VERSION 5.8 ;
BUSBITCHARS "[]" ;
DIVIDERCHAR "/" ;

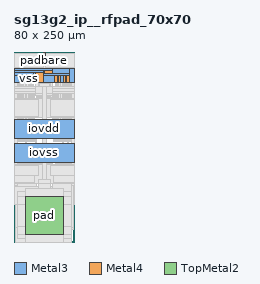
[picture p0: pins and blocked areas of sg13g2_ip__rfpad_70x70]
MACRO sg13g2_ip__rfpad_70x70
  CLASS PAD INOUT ;
  ORIGIN 0 0 ;
  FOREIGN sg13g2_ip__rfpad_70x70 0 0 ;
  SIZE 80.000 BY 250.000 ;
  SYMMETRY Y ;
  SITE sg13g2_ioSite ;
  PIN vss
    DIRECTION INOUT ;
    USE GROUND ;
    SHAPE ABUTMENT ;
    PORT
      LAYER Metal3 ;
      RECT 0.000 210.000 7.600 218.600 ;
      RECT 10.400 210.000 12.400 218.600 ;
      RECT 15.200 210.000 18.600 218.600 ;
      RECT 21.400 210.000 23.400 218.600 ;
      RECT 38.360 210.000 53.800 218.600 ;
      RECT 56.600 210.000 58.600 218.600 ;
      RECT 61.400 210.000 64.800 218.600 ;
      RECT 67.600 210.000 69.600 218.600 ;
      RECT 0.000 218.600 26.200 222.405 ;
      RECT 26.200 210.000 28.160 222.405 ;
      RECT 0.000 222.405 38.360 226.120 ;
      RECT 38.360 221.795 39.700 226.120 ;
      RECT 0.000 226.120 50.620 228.000 ;
      RECT 50.620 221.795 72.400 228.000 ;
      RECT 38.360 218.600 72.400 221.795 ;
      RECT 72.400 210.000 80.000 228.000 ;
    END
  END vss
  PIN vdd
    DIRECTION INOUT ;
    USE POWER ;
    SHAPE ABUTMENT ;
    PORT
      LAYER Metal4 ;
      RECT 0.000 210.000 80.000 225.800 ;
    END
  END vdd
  PIN iovss
    DIRECTION INOUT ;
    USE GROUND ;
    SHAPE ABUTMENT ;
    PORT
      LAYER Metal3 ;
      RECT 0.000 104.500 80.000 130.000 ;
    END
  END iovss
  PIN iovdd
    DIRECTION INOUT ;
    USE POWER ;
    SHAPE ABUTMENT ;
    PORT
      LAYER Metal3 ;
      RECT 0.000 136.000 80.000 161.500 ;
    END
  END iovdd
  PIN pad
    DIRECTION INOUT ;
    USE SIGNAL ;
    PORT
      LAYER TopMetal2 ;
      RECT 15.500 10.500 64.500 59.500 ;
    END
  END pad
  PIN padbare
    DIRECTION INOUT ;
    USE SIGNAL ;
    PORT
      LAYER TopMetal2 ;
      RECT 39.000 240.000 41.000 250.000 ;
    END
  END padbare
  OBS
    LAYER Metal1 ;
    RECT 16.270 113.880 16.730 123.340 ;
    RECT 55.070 96.130 55.930 126.610 ;
    RECT 55.070 126.610 74.030 127.470 ;
    RECT 73.170 96.130 74.030 126.610 ;
    RECT 55.070 95.270 74.030 96.130 ;
    RECT 37.520 137.070 40.280 137.370 ;
    RECT 39.320 157.630 42.080 157.930 ;
    RECT 39.320 163.870 42.080 164.170 ;
    RECT 37.520 184.430 40.280 184.730 ;
    RECT 17.450 83.015 27.370 83.225 ;
    RECT 27.370 113.645 28.230 114.530 ;
    RECT 17.450 113.435 38.150 113.645 ;
    RECT 27.370 103.505 28.230 113.435 ;
    RECT 17.450 103.295 38.150 103.505 ;
    RECT 27.370 93.365 28.230 103.295 ;
    RECT 17.450 93.155 38.150 93.365 ;
    RECT 28.230 83.015 38.150 83.225 ;
    RECT 27.370 82.130 28.230 93.155 ;
    RECT 5.630 103.295 15.550 103.505 ;
    RECT 5.630 123.575 15.550 123.785 ;
    RECT 5.630 113.435 15.550 113.645 ;
    RECT 5.630 93.155 15.550 93.365 ;
    RECT 5.630 83.015 15.550 83.225 ;
    RECT 0.970 82.130 5.630 124.670 ;
    RECT 0.970 133.730 4.830 198.790 ;
    RECT 52.570 133.730 53.430 198.790 ;
    RECT 0.970 198.790 27.430 199.650 ;
    RECT 26.570 132.870 27.430 198.790 ;
    RECT 0.970 199.650 4.830 228.030 ;
    RECT 40.050 103.295 49.970 103.505 ;
    RECT 17.450 123.575 27.370 123.785 ;
    RECT 0.970 124.670 28.230 125.530 ;
    RECT 0.970 125.530 4.830 132.870 ;
    RECT 0.970 132.870 26.570 133.730 ;
    RECT 40.050 113.435 49.970 113.645 ;
    RECT 28.230 114.530 50.830 115.390 ;
    RECT 49.970 81.270 50.830 114.530 ;
    RECT 4.830 73.040 29.030 80.530 ;
    RECT 0.970 73.040 4.830 82.130 ;
    RECT 4.830 81.270 49.970 82.130 ;
    RECT 40.050 83.015 49.970 83.225 ;
    RECT 40.050 93.155 49.970 93.365 ;
    RECT 27.370 114.530 28.230 124.670 ;
    RECT 52.570 132.870 75.170 133.730 ;
    RECT 52.570 198.790 75.170 199.650 ;
    RECT 75.170 16.388 78.030 19.248 ;
    RECT 75.170 19.248 78.030 228.030 ;
    RECT 78.030 49.970 79.030 228.030 ;
    RECT 50.970 0.000 75.170 16.388 ;
    RECT 50.970 16.388 75.170 80.530 ;
    RECT 0.970 49.970 50.970 73.040 ;
    RECT 1.970 0.000 50.970 19.248 ;
    RECT 1.970 19.248 50.970 49.970 ;
    RECT 57.450 118.675 72.150 118.885 ;
    RECT 57.450 119.815 72.150 120.025 ;
    RECT 57.450 120.955 72.150 121.165 ;
    RECT 57.450 122.095 72.150 122.305 ;
    RECT 57.450 114.115 72.150 114.325 ;
    RECT 57.450 123.235 72.150 123.445 ;
    RECT 57.450 124.375 72.150 124.585 ;
    RECT 57.450 125.515 72.150 125.725 ;
    RECT 54.450 134.445 63.350 134.655 ;
    RECT 54.420 135.720 63.380 136.400 ;
    RECT 57.450 115.255 72.150 115.465 ;
    RECT 54.450 137.465 63.350 137.675 ;
    RECT 54.420 138.740 63.380 139.420 ;
    RECT 54.450 140.485 63.350 140.695 ;
    RECT 54.420 141.760 63.380 142.440 ;
    RECT 54.450 143.505 63.350 143.715 ;
    RECT 54.420 144.780 63.380 145.460 ;
    RECT 54.450 146.525 63.350 146.735 ;
    RECT 54.420 147.800 63.380 148.480 ;
    RECT 54.450 149.545 63.350 149.755 ;
    RECT 54.420 150.820 63.380 151.500 ;
    RECT 54.450 152.565 63.350 152.775 ;
    RECT 54.420 153.840 63.380 154.520 ;
    RECT 54.450 155.585 63.350 155.795 ;
    RECT 54.420 156.860 63.380 157.540 ;
    RECT 54.450 158.605 63.350 158.815 ;
    RECT 54.420 159.880 63.380 160.560 ;
    RECT 54.450 161.625 63.350 161.835 ;
    RECT 54.420 162.900 63.380 163.580 ;
    RECT 57.450 116.395 72.150 116.605 ;
    RECT 54.450 164.645 63.350 164.855 ;
    RECT 54.420 165.920 63.380 166.600 ;
    RECT 54.450 167.665 63.350 167.875 ;
    RECT 54.420 168.940 63.380 169.620 ;
    RECT 54.450 170.685 63.350 170.895 ;
    RECT 54.420 171.960 63.380 172.640 ;
    RECT 54.450 173.705 63.350 173.915 ;
    RECT 54.420 174.980 63.380 175.660 ;
    RECT 54.450 176.725 63.350 176.935 ;
    RECT 54.420 178.000 63.380 178.680 ;
    RECT 54.450 179.745 63.350 179.955 ;
    RECT 54.420 181.020 63.380 181.700 ;
    RECT 54.450 182.765 63.350 182.975 ;
    RECT 54.420 184.040 63.380 184.720 ;
    RECT 54.450 185.785 63.350 185.995 ;
    RECT 54.420 187.060 63.380 187.740 ;
    RECT 54.450 188.805 63.350 189.015 ;
    RECT 54.420 190.080 63.380 190.760 ;
    RECT 54.450 191.825 63.350 192.035 ;
    RECT 54.420 193.100 63.380 193.780 ;
    RECT 54.450 194.845 63.350 195.055 ;
    RECT 54.420 196.120 63.380 196.800 ;
    RECT 54.450 197.865 63.350 198.075 ;
    RECT 57.450 117.535 72.150 117.745 ;
    RECT 64.070 174.150 64.530 174.710 ;
    RECT 65.220 181.020 74.180 181.700 ;
    RECT 64.070 181.970 64.530 182.530 ;
    RECT 65.220 171.960 74.180 172.640 ;
    RECT 65.250 182.765 74.150 182.975 ;
    RECT 64.070 183.210 64.530 183.770 ;
    RECT 65.220 174.980 74.180 175.660 ;
    RECT 65.220 184.040 74.180 184.720 ;
    RECT 64.070 184.990 64.530 185.550 ;
    RECT 64.070 175.930 64.530 176.490 ;
    RECT 65.250 185.785 74.150 185.995 ;
    RECT 64.070 186.230 64.530 186.790 ;
    RECT 64.070 172.910 64.530 173.470 ;
    RECT 65.220 187.060 74.180 187.740 ;
    RECT 64.070 188.010 64.530 188.570 ;
    RECT 65.250 176.725 74.150 176.935 ;
    RECT 65.250 188.805 74.150 189.015 ;
    RECT 64.070 189.250 64.530 189.810 ;
    RECT 64.070 177.170 64.530 177.730 ;
    RECT 65.220 190.080 74.180 190.760 ;
    RECT 64.070 191.030 64.530 191.590 ;
    RECT 64.070 171.130 64.530 171.690 ;
    RECT 65.250 191.825 74.150 192.035 ;
    RECT 64.070 192.270 64.530 192.830 ;
    RECT 65.220 178.000 74.180 178.680 ;
    RECT 65.220 193.100 74.180 193.780 ;
    RECT 64.070 194.050 64.530 194.610 ;
    RECT 64.070 178.950 64.530 179.510 ;
    RECT 65.250 194.845 74.150 195.055 ;
    RECT 64.070 195.290 64.530 195.850 ;
    RECT 65.250 173.705 74.150 173.915 ;
    RECT 65.220 196.120 74.180 196.800 ;
    RECT 64.070 197.070 64.530 197.630 ;
    RECT 65.250 179.745 74.150 179.955 ;
    RECT 65.250 197.865 74.150 198.075 ;
    RECT 64.070 180.190 64.530 180.750 ;
    RECT 44.720 184.430 47.480 184.730 ;
    RECT 48.320 184.430 51.080 184.730 ;
    RECT 44.380 192.870 45.970 221.280 ;
    RECT 42.100 191.800 43.690 222.190 ;
    RECT 42.100 222.190 48.250 223.660 ;
    RECT 46.630 191.800 48.250 222.190 ;
    RECT 42.100 190.330 48.250 191.800 ;
    RECT 40.270 189.850 41.680 224.140 ;
    RECT 40.270 224.140 50.050 225.550 ;
    RECT 48.670 189.850 50.050 224.140 ;
    RECT 40.270 188.440 50.050 189.850 ;
    RECT 41.120 184.430 43.880 184.730 ;
    RECT 42.920 163.870 45.680 164.170 ;
    RECT 56.570 116.790 57.030 117.350 ;
    RECT 46.520 163.870 49.280 164.170 ;
    RECT 50.090 157.600 51.110 164.200 ;
    RECT 41.120 137.070 43.880 137.370 ;
    RECT 44.720 137.070 47.480 137.370 ;
    RECT 48.320 137.070 51.080 137.370 ;
    RECT 56.570 123.630 57.030 124.190 ;
    RECT 56.570 121.350 57.030 121.910 ;
    RECT 56.570 124.770 57.030 125.330 ;
    RECT 56.570 115.650 57.030 116.210 ;
    RECT 42.920 157.630 45.680 157.930 ;
    RECT 46.520 157.630 49.280 157.930 ;
    RECT 56.570 117.930 57.030 118.490 ;
    RECT 56.570 114.510 57.030 115.070 ;
    RECT 56.570 122.490 57.030 123.050 ;
    RECT 56.570 120.210 57.030 120.770 ;
    RECT 56.570 119.070 57.030 119.630 ;
    RECT 64.070 136.670 64.530 137.230 ;
    RECT 65.220 156.860 74.180 157.540 ;
    RECT 65.220 141.760 74.180 142.440 ;
    RECT 64.070 142.710 64.530 143.270 ;
    RECT 64.070 134.890 64.530 135.450 ;
    RECT 64.070 157.810 64.530 158.370 ;
    RECT 65.250 143.505 74.150 143.715 ;
    RECT 65.250 158.605 74.150 158.815 ;
    RECT 64.070 159.050 64.530 159.610 ;
    RECT 64.070 143.950 64.530 144.510 ;
    RECT 65.220 159.880 74.180 160.560 ;
    RECT 64.070 160.830 64.530 161.390 ;
    RECT 65.250 137.465 74.150 137.675 ;
    RECT 65.250 161.625 74.150 161.835 ;
    RECT 64.070 162.070 64.530 162.630 ;
    RECT 65.220 144.780 74.180 145.460 ;
    RECT 65.220 162.900 74.180 163.580 ;
    RECT 64.070 145.730 64.530 146.290 ;
    RECT 64.070 137.910 64.530 138.470 ;
    RECT 65.250 146.525 74.150 146.735 ;
    RECT 64.070 146.970 64.530 147.530 ;
    RECT 64.070 163.850 64.530 164.410 ;
    RECT 65.250 134.445 74.150 134.655 ;
    RECT 65.250 164.645 74.150 164.855 ;
    RECT 64.070 165.090 64.530 165.650 ;
    RECT 65.220 147.800 74.180 148.480 ;
    RECT 65.220 165.920 74.180 166.600 ;
    RECT 64.070 166.870 64.530 167.430 ;
    RECT 64.070 148.750 64.530 149.310 ;
    RECT 65.250 167.665 74.150 167.875 ;
    RECT 64.070 168.110 64.530 168.670 ;
    RECT 65.220 138.740 74.180 139.420 ;
    RECT 65.220 168.940 74.180 169.620 ;
    RECT 64.070 169.890 64.530 170.450 ;
    RECT 65.250 149.545 74.150 149.755 ;
    RECT 65.250 170.685 74.150 170.895 ;
    RECT 64.070 149.990 64.530 150.550 ;
    RECT 64.070 139.690 64.530 140.250 ;
    RECT 65.220 150.820 74.180 151.500 ;
    RECT 64.070 151.770 64.530 152.330 ;
    RECT 65.220 135.720 74.180 136.400 ;
    RECT 65.250 152.565 74.150 152.775 ;
    RECT 64.070 153.010 64.530 153.570 ;
    RECT 65.250 140.485 74.150 140.695 ;
    RECT 65.220 153.840 74.180 154.520 ;
    RECT 64.070 154.790 64.530 155.350 ;
    RECT 64.070 140.930 64.530 141.490 ;
    RECT 65.250 155.585 74.150 155.795 ;
    RECT 64.070 156.030 64.530 156.590 ;
    RECT 16.620 165.920 25.580 166.600 ;
    RECT 16.620 150.820 25.580 151.500 ;
    RECT 16.620 141.760 25.580 142.440 ;
    RECT 16.650 167.665 25.550 167.875 ;
    RECT 16.620 168.940 25.580 169.620 ;
    RECT 16.650 152.565 25.550 152.775 ;
    RECT 16.650 137.465 25.550 137.675 ;
    RECT 16.650 170.685 25.550 170.895 ;
    RECT 16.620 171.960 25.580 172.640 ;
    RECT 16.620 153.840 25.580 154.520 ;
    RECT 16.650 143.505 25.550 143.715 ;
    RECT 16.650 173.705 25.550 173.915 ;
    RECT 16.620 174.980 25.580 175.660 ;
    RECT 16.650 155.585 25.550 155.795 ;
    RECT 16.650 176.725 25.550 176.935 ;
    RECT 16.620 178.000 25.580 178.680 ;
    RECT 16.620 156.860 25.580 157.540 ;
    RECT 16.620 144.780 25.580 145.460 ;
    RECT 16.650 179.745 25.550 179.955 ;
    RECT 16.620 181.020 25.580 181.700 ;
    RECT 16.620 138.740 25.580 139.420 ;
    RECT 16.650 182.765 25.550 182.975 ;
    RECT 16.620 184.040 25.580 184.720 ;
    RECT 16.650 158.605 25.550 158.815 ;
    RECT 16.650 146.525 25.550 146.735 ;
    RECT 16.620 159.880 25.580 160.560 ;
    RECT 16.650 185.785 25.550 185.995 ;
    RECT 16.620 187.060 25.580 187.740 ;
    RECT 16.620 135.720 25.580 136.400 ;
    RECT 16.650 161.625 25.550 161.835 ;
    RECT 16.650 188.805 25.550 189.015 ;
    RECT 16.620 147.800 25.580 148.480 ;
    RECT 16.620 190.080 25.580 190.760 ;
    RECT 16.620 162.900 25.580 163.580 ;
    RECT 16.650 191.825 25.550 192.035 ;
    RECT 16.650 140.485 25.550 140.695 ;
    RECT 16.620 193.100 25.580 193.780 ;
    RECT 16.650 134.445 25.550 134.655 ;
    RECT 16.650 194.845 25.550 195.055 ;
    RECT 16.650 149.545 25.550 149.755 ;
    RECT 16.620 196.120 25.580 196.800 ;
    RECT 16.650 197.865 25.550 198.075 ;
    RECT 16.650 164.645 25.550 164.855 ;
    RECT 33.920 184.430 36.680 184.730 ;
    RECT 30.320 184.430 33.080 184.730 ;
    RECT 33.910 192.870 35.770 221.280 ;
    RECT 31.750 191.800 33.370 222.190 ;
    RECT 31.750 222.190 37.900 223.660 ;
    RECT 36.310 191.800 37.900 222.190 ;
    RECT 31.750 190.330 37.900 191.800 ;
    RECT 29.950 189.850 31.330 224.140 ;
    RECT 29.950 224.140 39.730 225.550 ;
    RECT 38.320 189.850 39.730 224.140 ;
    RECT 29.950 188.440 39.730 189.850 ;
    RECT 5.820 174.980 14.780 175.660 ;
    RECT 15.470 186.230 15.930 186.790 ;
    RECT 5.820 187.060 14.780 187.740 ;
    RECT 5.850 179.745 14.750 179.955 ;
    RECT 15.470 172.910 15.930 173.470 ;
    RECT 15.470 188.010 15.930 188.570 ;
    RECT 15.470 180.190 15.930 180.750 ;
    RECT 5.850 188.805 14.750 189.015 ;
    RECT 5.820 181.020 14.780 181.700 ;
    RECT 15.470 171.130 15.930 171.690 ;
    RECT 15.470 189.250 15.930 189.810 ;
    RECT 5.820 190.080 14.780 190.760 ;
    RECT 15.470 175.930 15.930 176.490 ;
    RECT 15.470 191.030 15.930 191.590 ;
    RECT 15.470 181.970 15.930 182.530 ;
    RECT 5.850 191.825 14.750 192.035 ;
    RECT 5.850 182.765 14.750 182.975 ;
    RECT 5.850 176.725 14.750 176.935 ;
    RECT 15.470 192.270 15.930 192.830 ;
    RECT 5.820 193.100 14.780 193.780 ;
    RECT 15.470 183.210 15.930 183.770 ;
    RECT 15.470 194.050 15.930 194.610 ;
    RECT 5.820 184.040 14.780 184.720 ;
    RECT 5.850 194.845 14.750 195.055 ;
    RECT 5.850 173.705 14.750 173.915 ;
    RECT 15.470 177.170 15.930 177.730 ;
    RECT 15.470 195.290 15.930 195.850 ;
    RECT 5.820 196.120 14.780 196.800 ;
    RECT 5.820 178.000 14.780 178.680 ;
    RECT 15.470 197.070 15.930 197.630 ;
    RECT 5.850 197.865 14.750 198.075 ;
    RECT 5.820 171.960 14.780 172.640 ;
    RECT 15.470 174.150 15.930 174.710 ;
    RECT 15.470 184.990 15.930 185.550 ;
    RECT 15.470 178.950 15.930 179.510 ;
    RECT 5.850 185.785 14.750 185.995 ;
    RECT 5.820 141.760 14.780 142.440 ;
    RECT 5.850 167.665 14.750 167.875 ;
    RECT 15.470 166.870 15.930 167.430 ;
    RECT 5.850 161.625 14.750 161.835 ;
    RECT 15.470 169.890 15.930 170.450 ;
    RECT 15.470 154.790 15.930 155.350 ;
    RECT 5.850 134.445 14.750 134.655 ;
    RECT 15.470 142.710 15.930 143.270 ;
    RECT 5.820 147.800 14.780 148.480 ;
    RECT 5.820 138.740 14.780 139.420 ;
    RECT 5.850 155.585 14.750 155.795 ;
    RECT 15.470 162.070 15.930 162.630 ;
    RECT 5.850 170.685 14.750 170.895 ;
    RECT 15.470 145.730 15.930 146.290 ;
    RECT 5.850 140.485 14.750 140.695 ;
    RECT 5.820 162.900 14.780 163.580 ;
    RECT 15.470 151.770 15.930 152.330 ;
    RECT 15.470 153.010 15.930 153.570 ;
    RECT 15.470 157.810 15.930 158.370 ;
    RECT 15.470 137.910 15.930 138.470 ;
    RECT 5.850 158.605 14.750 158.815 ;
    RECT 15.470 148.750 15.930 149.310 ;
    RECT 15.470 136.670 15.930 137.230 ;
    RECT 15.470 143.950 15.930 144.510 ;
    RECT 5.850 137.465 14.750 137.675 ;
    RECT 5.850 146.525 14.750 146.735 ;
    RECT 5.820 153.840 14.780 154.520 ;
    RECT 15.470 156.030 15.930 156.590 ;
    RECT 15.470 168.110 15.930 168.670 ;
    RECT 5.850 149.545 14.750 149.755 ;
    RECT 15.470 159.050 15.930 159.610 ;
    RECT 5.820 135.720 14.780 136.400 ;
    RECT 15.470 134.890 15.930 135.450 ;
    RECT 5.820 159.880 14.780 160.560 ;
    RECT 5.820 156.860 14.780 157.540 ;
    RECT 15.470 163.850 15.930 164.410 ;
    RECT 15.470 140.930 15.930 141.490 ;
    RECT 5.850 152.565 14.750 152.775 ;
    RECT 5.850 164.645 14.750 164.855 ;
    RECT 5.820 168.940 14.780 169.620 ;
    RECT 5.850 143.505 14.750 143.715 ;
    RECT 15.470 139.690 15.930 140.250 ;
    RECT 15.470 149.990 15.930 150.550 ;
    RECT 15.470 146.970 15.930 147.530 ;
    RECT 5.820 144.780 14.780 145.460 ;
    RECT 15.470 165.090 15.930 165.650 ;
    RECT 15.470 160.830 15.930 161.390 ;
    RECT 5.820 150.820 14.780 151.500 ;
    RECT 5.820 165.920 14.780 166.600 ;
    RECT 32.120 157.630 34.880 157.930 ;
    RECT 30.320 137.070 33.080 137.370 ;
    RECT 35.720 157.630 38.480 157.930 ;
    RECT 28.490 125.970 29.510 137.400 ;
    RECT 30.320 163.870 31.280 164.170 ;
    RECT 28.520 157.630 31.280 157.930 ;
    RECT 33.920 137.070 36.680 137.370 ;
    RECT 32.120 163.870 34.880 164.170 ;
    RECT 35.720 163.870 38.480 164.170 ;
    RECT 16.270 83.460 16.730 92.920 ;
    RECT 38.870 83.460 39.330 92.920 ;
    RECT 16.270 93.600 16.730 103.060 ;
    RECT 38.870 93.600 39.330 103.060 ;
    RECT 16.270 103.740 16.730 113.200 ;
    RECT 38.870 103.740 39.330 113.200 ;
    RECT 57.450 102.715 72.150 102.925 ;
    RECT 57.700 84.155 71.900 84.365 ;
    RECT 56.570 84.550 57.030 85.110 ;
    RECT 56.570 103.110 57.030 103.670 ;
    RECT 57.450 103.855 72.150 104.065 ;
    RECT 56.570 104.250 57.030 104.810 ;
    RECT 57.450 104.995 72.150 105.205 ;
    RECT 56.570 105.390 57.030 105.950 ;
    RECT 57.450 106.135 72.150 106.345 ;
    RECT 56.570 106.530 57.030 107.090 ;
    RECT 57.450 107.275 72.150 107.485 ;
    RECT 56.570 107.670 57.030 108.230 ;
    RECT 57.450 108.415 72.150 108.625 ;
    RECT 56.570 108.810 57.030 109.370 ;
    RECT 57.450 109.555 72.150 109.765 ;
    RECT 56.570 109.950 57.030 110.510 ;
    RECT 57.450 110.695 72.150 110.905 ;
    RECT 56.570 111.090 57.030 111.650 ;
    RECT 57.450 111.835 72.150 112.045 ;
    RECT 56.570 112.230 57.030 112.790 ;
    RECT 57.450 112.975 72.150 113.185 ;
    RECT 57.700 85.295 71.900 85.505 ;
    RECT 56.570 85.690 57.030 86.250 ;
    RECT 56.570 113.370 57.030 113.930 ;
    RECT 57.700 86.435 71.900 86.645 ;
    RECT 56.570 86.830 57.030 87.390 ;
    RECT 57.700 87.575 71.900 87.785 ;
    RECT 56.570 87.970 57.030 88.530 ;
    RECT 57.700 88.715 71.900 88.925 ;
    RECT 56.570 89.110 57.030 89.670 ;
    RECT 57.700 89.855 71.900 90.065 ;
    RECT 56.570 90.250 57.030 90.810 ;
    RECT 57.700 90.995 71.900 91.205 ;
    RECT 56.570 91.390 57.030 91.950 ;
    RECT 57.700 92.135 71.900 92.345 ;
    RECT 57.700 83.015 71.900 83.225 ;
    RECT 56.570 83.410 57.030 83.970 ;
    RECT 55.070 82.130 55.930 93.230 ;
    RECT 55.070 93.230 72.920 94.090 ;
    RECT 72.920 82.130 73.780 94.090 ;
    RECT 55.070 81.270 73.780 82.130 ;
    RECT 57.450 97.015 72.150 97.225 ;
    RECT 56.570 97.410 57.030 97.970 ;
    RECT 57.450 98.155 72.150 98.365 ;
    RECT 56.570 98.550 57.030 99.110 ;
    RECT 57.450 99.295 72.150 99.505 ;
    RECT 56.570 99.690 57.030 100.250 ;
    RECT 57.450 100.435 72.150 100.645 ;
    RECT 56.570 100.830 57.030 101.390 ;
    RECT 57.450 101.575 72.150 101.785 ;
    RECT 56.570 101.970 57.030 102.530 ;
    LAYER Metal2 ;
    RECT 4.770 82.670 15.480 102.530 ;
    RECT 17.520 82.670 38.080 102.530 ;
    RECT 40.120 82.670 55.780 102.530 ;
    RECT 69.130 76.970 75.230 80.530 ;
    RECT 57.820 76.970 69.130 82.030 ;
    RECT 57.820 82.030 65.430 102.530 ;
    RECT 4.770 76.970 57.820 82.670 ;
    RECT 72.570 94.530 75.230 102.530 ;
    RECT 72.270 82.870 75.230 94.530 ;
    RECT 17.520 104.470 38.080 125.230 ;
    RECT 40.120 104.470 55.780 125.230 ;
    RECT 16.220 83.410 16.780 125.970 ;
    RECT 38.820 83.410 39.380 125.970 ;
    RECT 16.220 125.970 56.520 127.030 ;
    RECT 56.520 83.410 57.080 127.030 ;
    RECT 57.820 104.470 65.430 128.230 ;
    RECT 14.680 104.470 15.480 128.230 ;
    RECT 4.770 104.470 14.680 130.030 ;
    RECT 72.570 104.470 75.230 130.030 ;
    RECT 26.370 135.970 53.630 161.530 ;
    RECT 26.370 165.090 32.050 187.700 ;
    RECT 32.050 163.470 53.630 187.700 ;
    RECT 15.420 130.030 15.980 197.680 ;
    RECT 64.020 130.030 64.580 197.680 ;
    RECT 15.420 128.970 67.830 130.030 ;
    RECT 66.170 82.770 67.830 128.970 ;
    RECT 38.190 196.185 44.505 199.805 ;
    RECT 45.630 196.180 45.815 199.800 ;
    RECT 44.505 196.180 45.630 199.805 ;
    RECT 38.190 199.805 41.850 205.185 ;
    RECT 34.165 196.195 38.190 199.815 ;
    RECT 38.190 205.185 44.505 208.805 ;
    RECT 45.630 205.180 45.815 208.800 ;
    RECT 44.505 205.180 45.630 208.805 ;
    RECT 38.190 208.805 41.850 214.185 ;
    RECT 34.165 205.195 38.190 208.815 ;
    RECT 34.165 214.195 38.190 217.815 ;
    RECT 41.850 214.185 44.505 217.805 ;
    RECT 45.630 214.180 45.815 217.800 ;
    RECT 44.505 214.180 45.630 217.805 ;
    RECT 38.190 214.185 41.850 217.815 ;
    RECT 42.250 201.165 47.650 203.825 ;
    RECT 42.250 210.165 47.650 212.825 ;
    RECT 42.250 219.165 51.310 221.825 ;
    RECT 47.650 194.825 51.310 219.165 ;
    RECT 42.250 192.165 51.310 194.825 ;
    RECT 32.390 210.175 37.790 212.835 ;
    RECT 32.390 201.175 37.790 203.835 ;
    RECT 28.730 192.175 37.790 194.835 ;
    RECT 28.730 194.835 32.390 219.175 ;
    RECT 28.730 219.175 37.790 221.835 ;
    RECT 29.950 222.375 39.730 225.550 ;
    RECT 40.270 222.365 50.050 225.550 ;
    RECT 0.970 73.970 4.030 209.970 ;
    RECT 0.970 209.970 7.430 228.030 ;
    RECT 5.770 134.370 7.430 209.970 ;
    RECT 10.570 134.370 12.230 228.030 ;
    RECT 15.370 209.970 18.430 228.030 ;
    RECT 16.770 134.370 18.430 209.970 ;
    RECT 21.570 134.370 23.230 228.030 ;
    RECT 56.770 134.370 58.430 228.030 ;
    RECT 61.570 134.370 63.230 209.970 ;
    RECT 61.570 209.970 64.630 228.030 ;
    RECT 67.770 134.370 69.430 228.030 ;
    RECT 69.870 82.130 71.530 92.590 ;
    RECT 72.570 134.370 74.230 209.970 ;
    RECT 69.870 81.270 75.970 82.130 ;
    RECT 72.570 209.970 79.030 228.030 ;
    RECT 75.970 73.970 79.030 209.970 ;
    RECT 8.170 134.370 9.830 229.970 ;
    RECT 12.970 134.370 14.630 229.970 ;
    RECT 19.170 134.370 20.830 229.970 ;
    RECT 25.630 163.690 31.310 164.350 ;
    RECT 23.970 134.370 25.630 229.970 ;
    RECT 54.370 134.370 56.030 229.970 ;
    RECT 59.170 134.370 60.830 229.970 ;
    RECT 65.370 134.370 67.030 229.970 ;
    RECT 0.970 229.970 79.030 248.030 ;
    RECT 70.170 95.270 71.830 229.970 ;
    LAYER Metal3 ;
    RECT 4.970 4.105 27.197 20.488 ;
    RECT 4.970 20.488 10.814 22.202 ;
    RECT 4.970 22.202 9.100 47.808 ;
    RECT 4.970 47.808 10.814 49.522 ;
    RECT 4.970 49.522 27.197 65.905 ;
    RECT 21.353 65.905 58.647 70.040 ;
    RECT 69.186 47.808 75.030 49.522 ;
    RECT 52.803 49.522 75.030 65.905 ;
    RECT 70.900 22.202 75.030 47.808 ;
    RECT 52.803 4.105 75.030 20.488 ;
    RECT 69.186 20.488 75.030 22.202 ;
    RECT 21.353 0.000 58.647 4.105 ;
    RECT 0.000 76.970 80.000 102.530 ;
    RECT 0.000 163.470 80.000 189.030 ;
    RECT 0.000 195.970 80.000 204.030 ;
    RECT 34.165 204.570 45.815 209.430 ;
    RECT 8.170 209.970 9.830 218.030 ;
    RECT 12.970 209.970 14.630 218.030 ;
    RECT 19.170 209.970 20.830 218.030 ;
    RECT 23.970 209.970 25.630 218.030 ;
    RECT 54.370 209.970 56.030 218.030 ;
    RECT 59.170 209.970 60.830 218.030 ;
    RECT 65.370 209.970 67.030 218.030 ;
    RECT 70.170 209.970 71.830 218.030 ;
    RECT 28.730 209.970 37.790 221.835 ;
    RECT 40.270 222.365 50.050 225.550 ;
    RECT 0.000 229.970 80.000 248.030 ;
    LAYER Metal4 ;
    RECT 4.970 4.105 27.197 20.488 ;
    RECT 4.970 20.488 10.814 22.202 ;
    RECT 4.970 22.202 9.100 47.808 ;
    RECT 4.970 47.808 10.814 49.522 ;
    RECT 4.970 49.522 27.197 65.905 ;
    RECT 21.353 65.905 58.647 70.040 ;
    RECT 69.186 47.808 75.030 49.522 ;
    RECT 52.803 49.522 75.030 65.905 ;
    RECT 70.900 22.202 75.030 47.808 ;
    RECT 52.803 4.105 75.030 20.488 ;
    RECT 69.186 20.488 75.030 22.202 ;
    RECT 21.353 0.000 58.647 4.105 ;
    RECT 0.000 76.970 80.000 102.530 ;
    RECT 0.000 104.470 80.000 130.030 ;
    RECT 0.000 135.970 80.000 161.530 ;
    RECT 0.000 163.470 80.000 189.030 ;
    RECT 0.000 195.970 80.000 204.030 ;
    RECT 34.165 204.570 45.815 209.430 ;
    RECT 0.000 232.170 80.000 248.030 ;
    LAYER Metal5 ;
    RECT 4.970 4.105 27.197 20.488 ;
    RECT 4.970 20.488 10.814 22.202 ;
    RECT 4.970 22.202 9.100 47.808 ;
    RECT 4.970 47.808 10.814 49.522 ;
    RECT 4.970 49.522 27.197 65.905 ;
    RECT 21.353 65.905 58.647 70.040 ;
    RECT 69.186 47.808 75.030 49.522 ;
    RECT 52.803 49.522 75.030 65.905 ;
    RECT 70.900 22.202 75.030 47.808 ;
    RECT 52.803 4.105 75.030 20.488 ;
    RECT 69.186 20.488 75.030 22.202 ;
    RECT 21.353 0.000 58.647 4.105 ;
    RECT 0.000 76.970 80.000 102.530 ;
    RECT 0.000 104.470 80.000 130.030 ;
    RECT 0.000 135.970 80.000 161.530 ;
    RECT 0.000 163.470 80.000 189.030 ;
    RECT 0.000 195.970 80.000 204.030 ;
    RECT 34.165 204.570 45.815 209.430 ;
    RECT 0.000 209.970 80.000 228.030 ;
    RECT 0.000 229.970 80.000 248.030 ;
    LAYER TopMetal1 ;
    RECT 4.970 4.105 27.197 20.488 ;
    RECT 4.970 20.488 10.814 22.202 ;
    RECT 4.970 22.202 9.100 47.808 ;
    RECT 4.970 47.808 10.814 49.522 ;
    RECT 4.970 49.522 27.197 65.905 ;
    RECT 21.353 65.905 58.647 70.040 ;
    RECT 69.186 47.808 75.030 49.522 ;
    RECT 52.803 49.522 75.030 65.905 ;
    RECT 70.900 22.202 75.030 47.808 ;
    RECT 52.803 4.105 75.030 20.488 ;
    RECT 69.186 20.488 75.030 22.202 ;
    RECT 21.353 0.000 58.647 4.105 ;
    RECT 0.000 76.970 27.570 86.980 ;
    RECT 0.000 86.980 32.570 102.530 ;
    RECT 47.430 86.980 80.000 102.530 ;
    RECT 52.430 76.970 80.000 86.980 ;
    RECT 0.000 104.470 32.570 130.030 ;
    RECT 47.430 104.470 80.000 130.030 ;
    RECT 0.000 135.970 32.570 161.530 ;
    RECT 47.430 135.970 80.000 161.530 ;
    RECT 0.000 163.470 32.570 189.030 ;
    RECT 47.430 163.470 80.000 189.030 ;
    RECT 0.000 195.970 28.905 204.030 ;
    RECT 51.095 195.970 80.000 204.030 ;
    RECT 33.845 204.250 46.135 208.390 ;
    RECT 0.000 209.970 80.000 228.030 ;
    RECT 0.000 229.970 80.000 248.030 ;
    LAYER TopMetal2 ;
    RECT 0.000 78.470 27.570 86.980 ;
    RECT 0.000 86.980 32.570 101.030 ;
    RECT 47.430 86.980 80.000 101.030 ;
    RECT 52.430 78.470 80.000 86.980 ;
    RECT 0.000 105.970 32.570 128.530 ;
    RECT 47.430 105.970 80.000 128.530 ;
    RECT 0.000 137.470 32.570 160.030 ;
    RECT 47.430 137.470 80.000 160.030 ;
    RECT 0.000 164.970 32.570 187.530 ;
    RECT 47.430 164.970 80.000 187.530 ;
    RECT 0.000 197.470 28.905 202.530 ;
    RECT 51.095 197.470 80.000 202.530 ;
    RECT 4.970 10.500 15.500 20.488 ;
    RECT 4.970 20.488 15.500 49.522 ;
    RECT 4.970 49.522 15.500 59.500 ;
    RECT 38.970 240.000 39.000 240.030 ;
    RECT 14.948 59.500 64.500 60.052 ;
    RECT 15.500 60.052 64.500 70.040 ;
    RECT 64.500 10.500 75.030 20.488 ;
    RECT 64.500 20.488 75.030 49.522 ;
    RECT 64.500 49.522 75.030 60.052 ;
    RECT 14.958 0.000 65.042 10.500 ;
    RECT 32.510 70.040 47.490 77.022 ;
    RECT 32.510 77.022 47.490 82.022 ;
    RECT 37.510 82.022 42.490 204.250 ;
    RECT 33.845 204.250 46.135 208.390 ;
    RECT 41.030 208.390 42.490 210.030 ;
    RECT 41.000 208.390 41.030 240.030 ;
    RECT 38.970 210.030 41.000 240.000 ;
    RECT 37.510 208.390 41.000 210.030 ;
  END
END sg13g2_ip__rfpad_70x70

END LIBRARY
